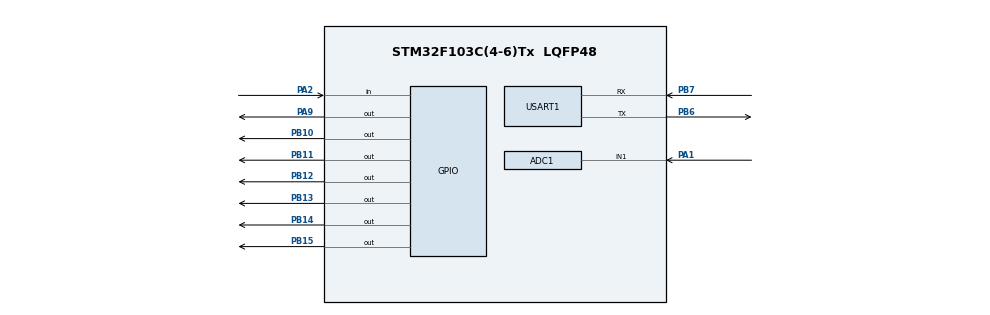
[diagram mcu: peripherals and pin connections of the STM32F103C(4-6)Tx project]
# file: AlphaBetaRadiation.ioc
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ADC1.Channel-2\#ChannelRegularConversion=ADC_CHANNEL_1
ADC1.NbrOfConversionFlag=1
ADC1.Rank-2\#ChannelRegularConversion=1
ADC1.SamplingTime-2\#ChannelRegularConversion=ADC_SAMPLETIME_1CYCLE_5
ADC1.master=1
Mcu.Family=STM32F1
Mcu.Name=STM32F103C(4-6)Tx
Mcu.Package=LQFP48
NVIC.PriorityGroup=NVIC_PRIORITYGROUP_4
PA1.Signal=ADCx_IN1
PA2.Signal=GPIO_Input
PA9.Signal=GPIO_Output
PB10.Signal=GPIO_Output
PB11.Signal=GPIO_Output
PB12.Signal=GPIO_Output
PB13.Signal=GPIO_Output
PB14.Signal=GPIO_Output
PB15.Signal=GPIO_Output
PB6.Mode=Asynchronous
PB6.Signal=USART1_TX
PB7.Mode=Asynchronous
PB7.Signal=USART1_RX
ProjectManager.HeapSize=0x200
ProjectManager.StackSize=0x400
ProjectManager.TargetToolchain=STM32CubeIDE
RCC.ADCPresc=RCC_ADCPCLK2_DIV6
RCC.AHBFreq_Value=64000000
RCC.APB1CLKDivider=RCC_HCLK_DIV2
RCC.APB1Freq_Value=32000000
RCC.APB1TimFreq_Value=64000000
RCC.APB2Freq_Value=64000000
RCC.APB2TimFreq_Value=64000000
RCC.HCLKFreq_Value=64000000
RCC.PLLMUL=RCC_PLL_MUL16
RCC.SYSCLKFreq_VALUE=64000000
RCC.SYSCLKSource=RCC_SYSCLKSOURCE_PLLCLK
RCC.USBFreq_Value=64000000
SH.ADCx_IN1.0=ADC1_IN1,IN1
TIM1.Period=65536 - 1
TIM1.Prescaler=64000 - 1
USART1.VirtualMode=VM_ASYNC
VP_SYS_VS_ND.Mode=No_Debug
VP_TIM1_VS_ClockSourceINT.Mode=Internal
board=custom

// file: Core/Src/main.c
/* USER CODE BEGIN Header */
/**
  ******************************************************************************
  * @file           : main.c
  * @brief          : Main program body
  ******************************************************************************
  * @attention
  *
  * <h2><center>&copy; Copyright (c) 2022 STMicroelectronics.
  * All rights reserved.</center></h2>
  *
  * This software component is licensed by ST under BSD 3-Clause license,
  * the "License"; You may not use this file except in compliance with the
  * License. You may obtain a copy of the License at:
  *                        opensource.org/licenses/BSD-3-Clause
  *
  ******************************************************************************
  */
/* USER CODE END Header */
#include "main.h"

/* USER CODE BEGIN Includes */
#include "stdio.h"
#include "string.h"
#include "lcd_txt.h"

/* USER CODE END Includes */

 ADC_HandleTypeDef hadc1;

TIM_HandleTypeDef htim1;

UART_HandleTypeDef huart1;

void SystemClock_Config(void);
static void MX_GPIO_Init(void);
static void MX_ADC1_Init(void);
static void MX_TIM1_Init(void);
static void MX_USART1_UART_Init(void);

int main(void)
{
  /* USER CODE BEGIN 1 */
	uint raw;
	uint adc_result;
	char alphabeta[100];
	uint loopcounter;
	char uart_buf[100];
	int uart_buf_len;
	int digi_val;
	uint16_t signal_above_threshold_flag;
	uint16_t signal_below_threshold_flag;

	float signal_moved_above_time;
	float signal_moved_below_time;

	float timer_val_start;
	float timer_val_end;

	uint16_t counter_flag;

	uint16_t threshold_counter;

	uint16_t amplitude_bw_LLD_ULD;
	uint16_t amplitude_greaterthan_ULD;
	uint16_t width_status;

	uint16_t no_of_alpha;
	uint16_t no_of_beta;

	float user_threshold_value;
	uint16_t max_amp;

	double pulse_width;

  /* USER CODE END 1 */

  /* MCU Configuration--------------------------------------------------------*/

  /* Reset of all peripherals, Initializes the Flash interface and the Systick. */
  HAL_Init();

  /* Configure the system clock */
  SystemClock_Config();

  /* Initialize all configured peripherals */
  MX_GPIO_Init();
  MX_ADC1_Init();
  MX_TIM1_Init();
  MX_USART1_UART_Init();
  /* USER CODE BEGIN 2 */
lcd_init();
loopcounter=0;
counter_flag=0;
threshold_counter=0;
user_threshold_value=2048;

signal_above_threshold_flag=10;
signal_below_threshold_flag=10;

signal_moved_below_time=10;
signal_moved_above_time=10;

pulse_width=0;

no_of_alpha=0;
no_of_beta=0;
max_amp=0;

//start timer
HAL_TIM_Base_Start(&htim1);
//get current counter
timer_val_start = __HAL_TIM_GET_COUNTER(&htim1);
  /* USER CODE END 2 */

  /* Infinite loop */
  while (1)
  {

    /* USER CODE BEGIN 3 */

	  //**********************ADC READING START*****************************

	  //Get ADC Value
	  HAL_ADC_Start(&hadc1);
	  HAL_ADC_PollForConversion(&hadc1,HAL_MAX_DELAY);
	  raw = HAL_ADC_GetValue(&hadc1);
	  HAL_Delay(20);

	  adc_result=raw;

	  //**********************ADC READING END***********************
	  loopcounter=loopcounter+1;

	  //**********************DIGITAL READING***********************

	  digi_val=HAL_GPIO_ReadPin (GPIOA, GPIO_PIN_2);

	  //**********************DIGITAL READING END*******************

	  //**********************Measuring pulse amplitude*************
	  if(adc_result>max_amp){
		  max_amp=adc_result;
	  }

	  //**********************Measuring pulse width*****************

	  	  //if(digi_val==0){
	  	    if(adc_result<410){
	  		signal_below_threshold_flag=1;
	  	  }

	  	  if(signal_below_threshold_flag==1){
	  		  //if(digi_val==1){
	  		  if(adc_result>410){
	  			  signal_moved_above_time = __HAL_TIM_GET_COUNTER(&htim1);
	  			  signal_above_threshold_flag=1;
	  			  signal_below_threshold_flag=0;
	  		  }
//	  		  else{
//				sprintf(alphabeta, "Signal: Below LLD \r \n");
//
//				uart_buf_len = sprintf(uart_buf, "PA < LLD \r\n");
//				lcd_puts(1,0,(int8_t*)uart_buf);
//	  		  }
	  	  }
	  		if(signal_above_threshold_flag==1){
	  			//if(digi_val==0){
	  			if(adc_result<410){
	  			  signal_moved_below_time = __HAL_TIM_GET_COUNTER(&htim1);
	  			  signal_below_threshold_flag=1;
	  			  signal_above_threshold_flag=0;
	  			  pulse_width = (signal_moved_below_time - signal_moved_above_time)/100;

	  			  uart_buf_len = sprintf(uart_buf, "PW %f \r\n", pulse_width);
	  			  //HAL_UART_Transmit(&huart1,(uint8_t*)uart_buf,strlen(uart_buf),HAL_MAX_DELAY);
	  			  lcd_puts(0,0,(int8_t*)uart_buf);

	  			  uart_buf_len = sprintf(uart_buf, "Max Amp %u \r\n", max_amp);
	  			  HAL_UART_Transmit(&huart1,(uint8_t*)uart_buf,strlen(uart_buf),HAL_MAX_DELAY);

	  			  //uart_buf_len = sprintf(uart_buf, "PA %f \r\n", max_amp);
	  			  //lcd_puts(1,0,(int8_t*)uart_buf);

	  	  		if(max_amp>2048){
	  	  			if(pulse_width>0.5){
	  	  				sprintf(alphabeta, "Signal: Alpha \r \n");
	  	  				no_of_alpha=no_of_alpha+1;
	  	  			}
	  	  			if(pulse_width<0.5){
	  	  				sprintf(alphabeta, "Signal: Beta \r \n");
	  	  				no_of_beta=no_of_beta+1;
	  	  			}

	  	  			uart_buf_len = sprintf(uart_buf, "PA > ULD \r\n");
	  	  			lcd_puts(1,0,(int8_t*)uart_buf);
	  	  		}
	  	  		//if(max_amp<410){
	  	  		else if(max_amp>410){
	  	  			if(max_amp<2048){

	  	  			sprintf(alphabeta, "SIGNAL: Beta \r \n");
	  	  			no_of_beta=no_of_beta+1;

	  	  			uart_buf_len = sprintf(uart_buf, "LLD<PA<ULD \r\n");
	  	  			lcd_puts(1,0,(int8_t*)uart_buf);
	  	  			}
	  	  		}

	  	  		max_amp=0;
			  }
		  }

	  //**********************Measuring pulse width ended**********************

	  uart_buf_len = sprintf(uart_buf, alphabeta);
	  //HAL_UART_Transmit(&huart1,(uint8_t*)uart_buf,strlen(uart_buf),HAL_MAX_DELAY);

	  //uart_buf_len = sprintf(uart_buf, "Digi %u \r\n", digi_val);

      //lcd_puts(0,0,(int8_t*)uart_buf);

      timer_val_end = __HAL_TIM_GET_COUNTER(&htim1);
      if((timer_val_end - timer_val_start) > 100){
    	  timer_val_start=__HAL_TIM_GET_COUNTER(&htim1);
    	  uart_buf_len = sprintf(uart_buf, "No of Beta pulse/sec: %u \r \n",no_of_beta);
    	  HAL_UART_Transmit(&huart1,(uint8_t*)uart_buf,strlen(uart_buf),HAL_MAX_DELAY);

    	  uart_buf_len = sprintf(uart_buf, "No of Alpha pulse/sec: %u \r \n",no_of_alpha);
    	  HAL_UART_Transmit(&huart1,(uint8_t*)uart_buf,strlen(uart_buf),HAL_MAX_DELAY);

    	  uart_buf_len = sprintf(uart_buf, "********************************** \r \n");
    	  HAL_UART_Transmit(&huart1,(uint8_t*)uart_buf,strlen(uart_buf),HAL_MAX_DELAY);

    	  no_of_alpha=0;
    	  no_of_beta=0;
      }
      //HAL_Delay();
      //lcd_clear();
  }
  /* USER CODE END 3 */
}

void SystemClock_Config(void)
{
  RCC_OscInitTypeDef RCC_OscInitStruct = {0};
  RCC_ClkInitTypeDef RCC_ClkInitStruct = {0};
  RCC_PeriphCLKInitTypeDef PeriphClkInit = {0};

  /** Initializes the RCC Oscillators according to the specified parameters
  * in the RCC_OscInitTypeDef structure.
  */
  RCC_OscInitStruct.OscillatorType = RCC_OSCILLATORTYPE_HSI;
  RCC_OscInitStruct.HSIState = RCC_HSI_ON;
  RCC_OscInitStruct.HSICalibrationValue = RCC_HSICALIBRATION_DEFAULT;
  RCC_OscInitStruct.PLL.PLLState = RCC_PLL_NONE;
  if (HAL_RCC_OscConfig(&RCC_OscInitStruct) != HAL_OK)
  {
    Error_Handler();
  }

  /** Initializes the CPU, AHB and APB buses clocks
  */
  RCC_ClkInitStruct.ClockType = RCC_CLOCKTYPE_HCLK|RCC_CLOCKTYPE_SYSCLK
                              |RCC_CLOCKTYPE_PCLK1|RCC_CLOCKTYPE_PCLK2;
  RCC_ClkInitStruct.SYSCLKSource = RCC_SYSCLKSOURCE_HSI;
  RCC_ClkInitStruct.AHBCLKDivider = RCC_SYSCLK_DIV1;
  RCC_ClkInitStruct.APB1CLKDivider = RCC_HCLK_DIV1;
  RCC_ClkInitStruct.APB2CLKDivider = RCC_HCLK_DIV1;

  if (HAL_RCC_ClockConfig(&RCC_ClkInitStruct, FLASH_LATENCY_0) != HAL_OK)
  {
    Error_Handler();
  }
  PeriphClkInit.PeriphClockSelection = RCC_PERIPHCLK_ADC;
  PeriphClkInit.AdcClockSelection = RCC_ADCPCLK2_DIV2;
  if (HAL_RCCEx_PeriphCLKConfig(&PeriphClkInit) != HAL_OK)
  {
    Error_Handler();
  }
}

static void MX_ADC1_Init(void)
{

  ADC_ChannelConfTypeDef sConfig = {0};

  /** Common config
  */
  hadc1.Instance = ADC1;
  hadc1.Init.ScanConvMode = ADC_SCAN_DISABLE;
  hadc1.Init.ContinuousConvMode = DISABLE;
  hadc1.Init.DiscontinuousConvMode = DISABLE;
  hadc1.Init.ExternalTrigConv = ADC_SOFTWARE_START;
  hadc1.Init.DataAlign = ADC_DATAALIGN_RIGHT;
  hadc1.Init.NbrOfConversion = 1;
  if (HAL_ADC_Init(&hadc1) != HAL_OK)
  {
    Error_Handler();
  }

  /** Configure Regular Channel
  */
  sConfig.Channel = ADC_CHANNEL_1;
  sConfig.Rank = ADC_REGULAR_RANK_1;
  sConfig.SamplingTime = ADC_SAMPLETIME_1CYCLE_5;
  if (HAL_ADC_ConfigChannel(&hadc1, &sConfig) != HAL_OK)
  {
    Error_Handler();
  }

}

static void MX_TIM1_Init(void)
{

  TIM_ClockConfigTypeDef sClockSourceConfig = {0};
  TIM_MasterConfigTypeDef sMasterConfig = {0};

  htim1.Instance = TIM1;
  htim1.Init.Prescaler = 64000 - 1;
  htim1.Init.CounterMode = TIM_COUNTERMODE_UP;
  htim1.Init.Period = 65536 - 1;
  htim1.Init.ClockDivision = TIM_CLOCKDIVISION_DIV1;
  htim1.Init.RepetitionCounter = 0;
  htim1.Init.AutoReloadPreload = TIM_AUTORELOAD_PRELOAD_DISABLE;
  if (HAL_TIM_Base_Init(&htim1) != HAL_OK)
  {
    Error_Handler();
  }
  sClockSourceConfig.ClockSource = TIM_CLOCKSOURCE_INTERNAL;
  if (HAL_TIM_ConfigClockSource(&htim1, &sClockSourceConfig) != HAL_OK)
  {
    Error_Handler();
  }
  sMasterConfig.MasterOutputTrigger = TIM_TRGO_RESET;
  sMasterConfig.MasterSlaveMode = TIM_MASTERSLAVEMODE_DISABLE;
  if (HAL_TIMEx_MasterConfigSynchronization(&htim1, &sMasterConfig) != HAL_OK)
  {
    Error_Handler();
  }

}

static void MX_USART1_UART_Init(void)
{

  huart1.Instance = USART1;
  huart1.Init.BaudRate = 115200;
  huart1.Init.WordLength = UART_WORDLENGTH_8B;
  huart1.Init.StopBits = UART_STOPBITS_1;
  huart1.Init.Parity = UART_PARITY_NONE;
  huart1.Init.Mode = UART_MODE_TX_RX;
  huart1.Init.HwFlowCtl = UART_HWCONTROL_NONE;
  huart1.Init.OverSampling = UART_OVERSAMPLING_16;
  if (HAL_UART_Init(&huart1) != HAL_OK)
  {
    Error_Handler();
  }

}

static void MX_GPIO_Init(void)
{
  GPIO_InitTypeDef GPIO_InitStruct = {0};

  /* GPIO Ports Clock Enable */
  __HAL_RCC_GPIOA_CLK_ENABLE();
  __HAL_RCC_GPIOB_CLK_ENABLE();

  /*Configure GPIO pin Output Level */
  HAL_GPIO_WritePin(GPIOB, GPIO_PIN_10|GPIO_PIN_11|GPIO_PIN_12|GPIO_PIN_13
                          |GPIO_PIN_14|GPIO_PIN_15, GPIO_PIN_RESET);

  /*Configure GPIO pin Output Level */
  HAL_GPIO_WritePin(GPIOA, GPIO_PIN_9, GPIO_PIN_RESET);

  /*Configure GPIO pin : PA2 */
  GPIO_InitStruct.Pin = GPIO_PIN_2;
  GPIO_InitStruct.Mode = GPIO_MODE_INPUT;
  GPIO_InitStruct.Pull = GPIO_NOPULL;
  HAL_GPIO_Init(GPIOA, &GPIO_InitStruct);

  /*Configure GPIO pins : PB10 PB11 PB12 PB13
                           PB14 PB15 */
  GPIO_InitStruct.Pin = GPIO_PIN_10|GPIO_PIN_11|GPIO_PIN_12|GPIO_PIN_13
                          |GPIO_PIN_14|GPIO_PIN_15;
  GPIO_InitStruct.Mode = GPIO_MODE_OUTPUT_PP;
  GPIO_InitStruct.Pull = GPIO_NOPULL;
  GPIO_InitStruct.Speed = GPIO_SPEED_FREQ_LOW;
  HAL_GPIO_Init(GPIOB, &GPIO_InitStruct);

  /*Configure GPIO pin : PA9 */
  GPIO_InitStruct.Pin = GPIO_PIN_9;
  GPIO_InitStruct.Mode = GPIO_MODE_OUTPUT_PP;
  GPIO_InitStruct.Pull = GPIO_NOPULL;
  GPIO_InitStruct.Speed = GPIO_SPEED_FREQ_LOW;
  HAL_GPIO_Init(GPIOA, &GPIO_InitStruct);

}

void Error_Handler(void)
{
}
